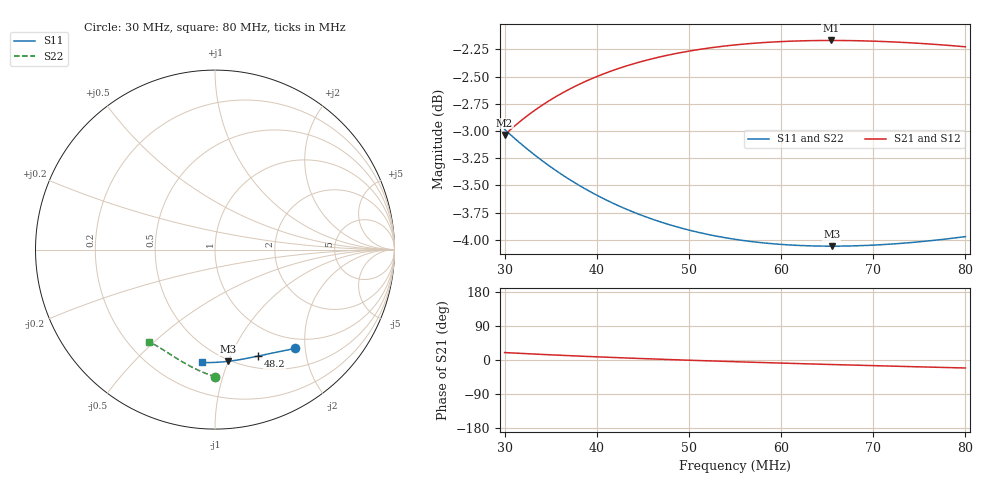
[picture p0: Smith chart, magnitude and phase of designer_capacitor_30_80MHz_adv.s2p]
! Touchstone file exported from Circuit Design 2018.2.0
!  File:  C:/Users/JH218595/Documents/scikit-rf/doc/source/examples/circuit/examples_circuits.aedt
!  Generated:  5:28:43  avr. 28, 2019
!  Design:  capacitor_eqmodel_adv
!  Project:  examples_circuits
!  Setup:  LinearFrequency
!  Solution:  LinearFrequency
! Variables:
!  C = 70pF
!Data is not renormalized
# GHZ S MA
! Modal data exported
! Port[1] = Port1
! Port[2] = Port2
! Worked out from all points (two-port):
!   501 points, 30 MHz to 80 MHz, reference per port
!   highest |S21| = -2.17 dB at 65.4 MHz (marker M1); lowest = -3.0 dB at 30 MHz (marker M2)
!   |S21| within 3 dB of the highest: start of sweep to end of sweep
!   lowest |S11| = -4.1 dB at 65.5 MHz (marker M3), VSWR 4.36
!   |S11| at or under -10 dB: nowhere
!   |S22| runs from -4.1 to -3.0 dB; largest |S21 - S12| = 1.7e-15
!   S11 on the Smith chart (normalised r, x): 30 MHz: 0.82, -1.81; 48.2 MHz: 0.64, -1.28; 80 MHz: 0.39, -0.81
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0.03  0.7092 -50.8  0.705 19.6  0.705 19.6  0.7092 -89.8
! Port Impedance50 0 50 0
0.0302  0.7079 -51.0  0.7062 19.4  0.7062 19.4  0.7079 -90.2
0.0312  0.7017 -52.0  0.7124 18.1  0.7124 18.1  0.7018 -91.7
0.0323  0.6954 -53.1  0.7185 16.8  0.7185 16.8  0.6954 -93.3
0.0342  0.6854 -55.0  0.7281 14.5  0.7281 14.5  0.6854 -95.9
0.0362  0.6761 -56.9  0.7367 12.3  0.7367 12.3  0.6761 -98.5
0.0384  0.6672 -58.9  0.7448 10.0  0.7448 10.0  0.6672 -101.1
0.0404  0.6601 -60.8  0.7511 8.0  0.7511 8.0  0.6601 -103.3
0.0424  0.654 -62.6  0.7564 6.0  0.7564 6.0  0.654 -105.3
0.0445  0.6484 -64.5  0.7612 4.1  0.7612 4.1  0.6484 -107.2
0.0467  0.6434 -66.5  0.7654 2.2  0.7654 2.2  0.6435 -109.1
0.0482  0.6405 -67.9  0.7678 0.9  0.7678 0.9  0.6406 -110.3
0.0515  0.6353 -70.8  0.7722 -1.8  0.7722 -1.8  0.6353 -112.8
0.055  0.6313 -74.0  0.7754 -4.5  0.7754 -4.5  0.6313 -115.0
0.0591  0.6283 -77.7  0.7778 -7.5  0.7778 -7.5  0.6284 -117.4
0.0634  0.6269 -81.5  0.779 -10.5  0.779 -10.5  0.627 -119.5
0.0654  0.6267 -83.4  0.7791 -11.9  0.7791 -11.9  0.6268 -120.4
0.0655  0.6267 -83.4  0.7791 -12.0  0.7791 -12.0  0.6268 -120.5
0.0685  0.627 -86.1  0.7788 -13.9  0.7788 -13.9  0.6271 -121.7
0.0717  0.628 -89.0  0.7781 -16.0  0.7781 -16.0  0.6281 -122.9
0.0763  0.6304 -93.2  0.7761 -18.9  0.7761 -18.9  0.6305 -124.5
0.08  0.6331 -96.5  0.7739 -21.1  0.7739 -21.1  0.6332 -125.6
